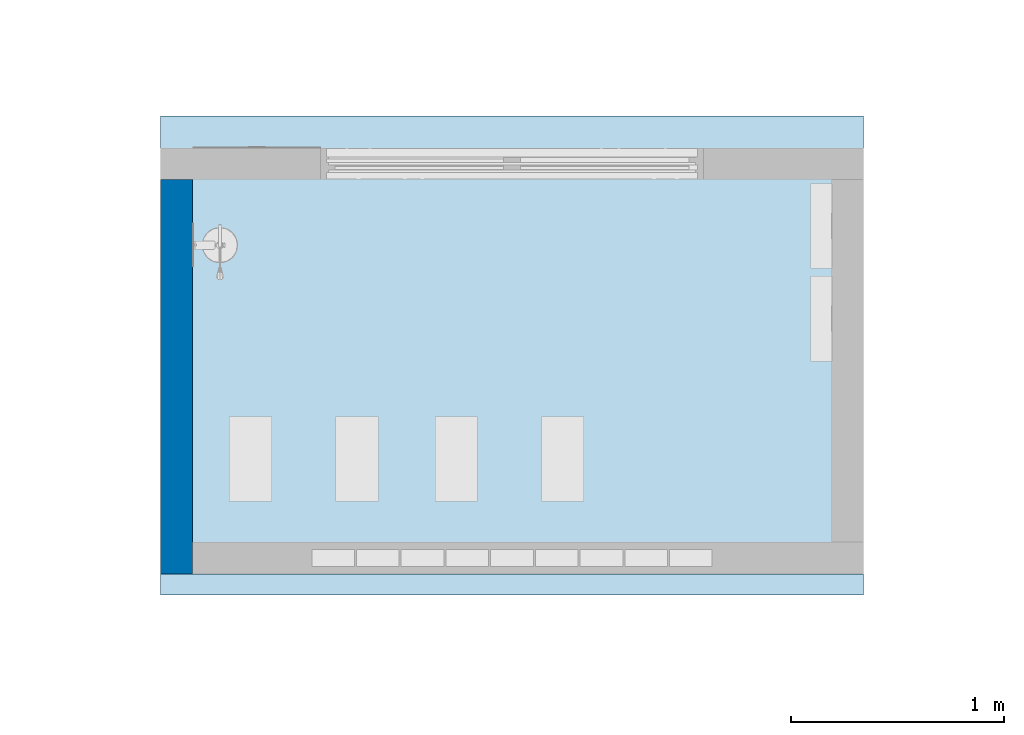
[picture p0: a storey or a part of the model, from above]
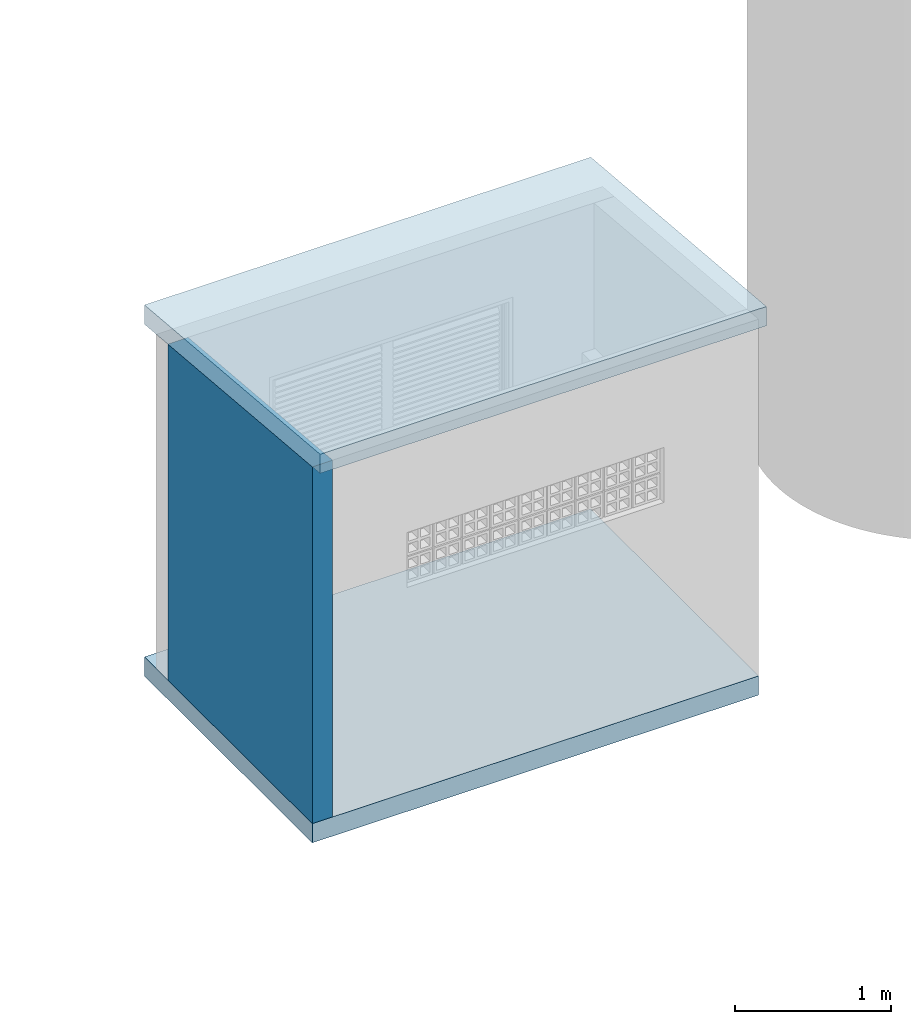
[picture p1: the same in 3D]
Properties of the parts of a building model (IFC2X3)

# File
Description: ViewDefinition [CoordinationView_V2.0]
File name: 0001
Time: 2022-03-27T23:40:12
Written by: The EXPRESS Data Manager Version 5.02.0100.07 : 28 Aug 2013
Made in: 21.1.60.25 - Exporter 21.1.60.25 - IU alternativa 21.1.60.25
Comment: STEP Physical File produced by: The EXPRESS Data Manager Version 5.02.0100.07 : 28 Aug 2013 * Module: EDMstepFileFactory/EDMstandAlone * Creation date: Sun Mar 27 23:40:12 2022 * Host: DESKTOP-MK1 * Database: C:\Users\kahal\AppData\Local\Temp\8a390837-8d56-472b-9c78-61db43efe1cc\653d68c4-2501-4b75-b9e8-e501fac27b86\ifc * Database version: 5507 * Database creation date: Sun Mar 27 23:39:55 2022 * Schema: IFC2X3 * Model: DataRepository.ifc * Model creation date: Sun Mar 27 23:39:55 2022 * Header model: DataRepository.ifc_HeaderModel * Header model creation date: Sun Mar 27 23:39:55 2022 * EDMuser: sdai-user * EDMgroup: sdai-group * License ID and type: 5605 : Permanent license. Expiry date: * EDMstepFileFactory options: 020000

# IfcProject, 0001
LongName: PROJETO DE SEGURANÇA CONTRA INCÊNDIO E PÂNICO; Phase: Status do projeto

# IfcSite, Default
RefLatitude: 42, 12, 46, 804504; RefLongitude: -71, -2, 0, -602416; RefElevation: 0 m

# IfcBuilding
Pset_BuildingCommon - NumberOfStoreys: 1

# IfcBuildingStorey: Nível:QDCG, PAV. 01 - TÉRREO
LongName: PAV. 01 - TÉRREO; Elevation: 0 m

# IfcBuildingElementProxy: CAIXA D'ÁGUA TIPO TUBULAR1:85m3 - TBL - 15,00m, CAIXA D'ÁGUA TIPO TUBULAR1:85m3 - TBL - 15,00m:11374999
In: PAV. 01 - TÉRREO
Type - Material: Material_reservatório
Type - Pset_BuildingElementProxyCommon - Reference: 85m3 - TBL - 15,00m
Type - Pset_QuantityTakeOff - Reference: 85m3 - TBL - 15,00m
Pset_BuildingElementProxyCommon - sets with these values: 2
Pset_ProvisionForVoid - Width: 15 m; Depth: 15 m

# IfcBuildingElementProxy: CAMINHÃO DE BOMBEIRO:CAMINHÃO DE BOMBEIRO, CAMINHÃO DE BOMBEIRO:CAMINHÃO DE BOMBEIRO:11451296
In: PAV. 01 - TÉRREO
Type - Material: Metal - Con capa pulverizada blanca
Type - Pset_BuildingElementProxyCommon - Reference: CAMINHÃO DE BOMBEIRO
Type - Pset_QuantityTakeOff - Reference: CAMINHÃO DE BOMBEIRO
Material: Metal - Con capa pulverizada blanca, Goma, Pintura - Extintor negro, Pintura - Extintor rojo, Metal - Aluminio, Fanalini rossi man, Body auto man, acciaio auto man, Fanalini arancioni man, Parti in plastica nere man, PINTURA CAMION RED, pedana martellata man, Nero ruote man, Acciaio cerchi man, Nero autocarro man, Vetro fari man, Vetro autocarro man
Pset_BuildingElementProxyCommon - sets with these values: 2

# IfcBuildingElementProxy: Elemento - E01-E02 - Alarme Sonoro + Comando manual do alarme:Alarme sonoro e botoeira do alarme (4)
In: PAV. 01 - TÉRREO
Type - Material: Plastico vermelho
Type - Pset_BuildingElementProxyCommon - Reference: Alarme sonoro e botoeira do alarme
Type - Pset_QuantityTakeOff - Reference: Alarme sonoro e botoeira do alarme
Material: Plastico vermelho, UHMW, White, Black, UHMW, Black, Plastic - Green Generic
Pset_BuildingElementProxyCommon - sets with these values: 2
Name (Elemento - E01-E02 - Alarme Sonoro + Comando manual do alarme:Alarme sonoro e botoeira do alarme:...)
11580355
11580449
11582165
11583381

# IfcBuildingElementProxy: Elemento - E03 - Comando manual de bomba:Botoeira da bomba (4)
In: PAV. 01 - TÉRREO
Type - Material: Plastico vermelho
Type - Pset_BuildingElementProxyCommon - Reference: Botoeira da bomba
Type - Pset_ManufacturerTypeInformation - Manufacturer: advCOMM
Type - Pset_QuantityTakeOff - Reference: Botoeira da bomba
Material: Plastico vermelho, UHMW, White, Black, UHMW, Black
Pset_BuildingElementProxyCommon - sets with these values: 2
Name (Elemento - E03 - Comando manual de bomba:Botoeira da bomba:...)
11580344
11580447
11582163
11583370

# IfcBuildingElementProxy: Elemento - E05 - Extintor:Extintor na parede - Carga de Pó ABC - 06Kg 3-A 20-BC (20)
In: PAV. 01 - TÉRREO
Type - Material: Plastico vermelho
Type - Pset_BuildingElementProxyCommon - Reference: Extintor na parede - Carga de Pó ABC - 06Kg 3-A 20-BC
Type - Pset_ManufacturerTypeInformation - Manufacturer: advCOMM
Type - Pset_QuantityTakeOff - Reference: Extintor na parede - Carga de Pó ABC - 06Kg 3-A 20-BC
Pset_BuildingElementProxyCommon - sets with these values: 2
Name (Elemento - E05 - Extintor:Extintor na parede - Carga de Pó ABC - 06Kg 3-A 20-BC:...) | Material
11374114 | Plastico vermelho, Plastico Amarelo, Pintura branca, Vidro, Pintura Metalica Vermelha, Metal Extintor, Borracha Cinza, Borracha preta, Plastico branco
11374170 | Plastico vermelho, Plastico Amarelo, Pintura branca, Vidro, Pintura Metalica Vermelha, Metal Extintor, Borracha Cinza, Borracha preta, Plastico branco
11565246 | Plastico vermelho, Plastico Amarelo, Pintura branca, Vidro, Pintura Metalica Vermelha, Metal Extintor, Borracha Cinza, Borracha preta, Plastico branco
11565351 | Plastico vermelho, Plastico Amarelo, Pintura branca, Vidro, Pintura Metalica Vermelha, Metal Extintor, Borracha Cinza, Borracha preta, Plastico branco
11578997 | Plastico vermelho, Plastico Amarelo, Metal Extintor, Borracha Cinza, Borracha preta, Plastico branco, Pintura Metalica Vermelha
11579091 | Plastico vermelho, Plastico Amarelo, Metal Extintor, Borracha Cinza, Borracha preta, Plastico branco, Pintura Metalica Vermelha
11579269 | Plastico vermelho, Plastico Amarelo, Metal Extintor, Borracha Cinza, Borracha preta, Plastico branco, Pintura Metalica Vermelha
11579494 | Plastico vermelho, Plastico Amarelo, Metal Extintor, Borracha Cinza, Borracha preta, Plastico branco, Pintura Metalica Vermelha
11580399 | Plastico vermelho, Plastico Amarelo, Metal Extintor, Borracha Cinza, Borracha preta, Plastico branco, Pintura Metalica Vermelha
11580481 | Plastico vermelho, Plastico Amarelo, Metal Extintor, Borracha Cinza, Borracha preta, Plastico branco, Pintura Metalica Vermelha
11580532 | Plastico vermelho, Plastico Amarelo, Metal Extintor, Borracha Cinza, Borracha preta, Plastico branco, Pintura Metalica Vermelha
11580586 | Plastico vermelho, Plastico Amarelo, Metal Extintor, Borracha Cinza, Borracha preta, Plastico branco, Pintura Metalica Vermelha
11581259 | Plastico vermelho, Plastico Amarelo, Metal Extintor, Borracha Cinza, Borracha preta, Plastico branco, Pintura Metalica Vermelha
11582185 | Plastico vermelho, Plastico Amarelo, Metal Extintor, Borracha Cinza, Borracha preta, Plastico branco, Pintura Metalica Vermelha
11583005 | Plastico vermelho, Plastico Amarelo, Metal Extintor, Borracha Cinza, Borracha preta, Plastico branco, Pintura Metalica Vermelha
11583127 | Plastico vermelho, Plastico Amarelo, Metal Extintor, Borracha Cinza, Borracha preta, Plastico branco, Pintura Metalica Vermelha
11583312 | Plastico vermelho, Plastico Amarelo, Metal Extintor, Borracha Cinza, Borracha preta, Plastico branco, Pintura Metalica Vermelha
11583412 | Plastico vermelho, Plastico Amarelo, Metal Extintor, Borracha Cinza, Borracha preta, Plastico branco, Pintura Metalica Vermelha
11583428 | Plastico vermelho, Plastico Amarelo, Metal Extintor, Borracha Cinza, Borracha preta, Plastico branco, Pintura Metalica Vermelha
11583605 | Plastico vermelho, Plastico Amarelo, Metal Extintor, Borracha Cinza, Borracha preta, Plastico branco, Pintura Metalica Vermelha

# IfcBuildingElementProxy: Elemento - E05 - Extintor:Extintor na parede - Carga de Pó BC - 06Kg 20-BC, Elemento - E05 - Extintor:Extintor na parede - Carga de Pó BC - 06Kg 20-BC:11376019
In: PAV. 01 - TÉRREO
Type - Material: Metal Extintor
Type - Pset_BuildingElementProxyCommon - Reference: Extintor na parede - Carga de Pó BC - 06Kg 20-BC
Type - Pset_ManufacturerTypeInformation - Manufacturer: advCOMM
Type - Pset_QuantityTakeOff - Reference: Extintor na parede - Carga de Pó BC - 06Kg 20-BC
Material: Metal Extintor, Borracha Cinza, Borracha preta, Plastico branco, Pintura Metalica Vermelha
Pset_BuildingElementProxyCommon - sets with these values: 2

# IfcBuildingElementProxy: Elemento - E05 - Extintor:Extintor na parede - Carga de Pó BC - 06Kg 20-BC, Elemento - E05 - Extintor:Extintor na parede - Carga de Pó BC - 06Kg 20-BC:11578051
In: PAV. 01 - TÉRREO
Type - Material: Pintura branca
Type - Pset_BuildingElementProxyCommon - Reference: Extintor na parede - Carga de Pó BC - 06Kg 20-BC
Type - Pset_ManufacturerTypeInformation - Manufacturer: advCOMM
Type - Pset_QuantityTakeOff - Reference: Extintor na parede - Carga de Pó BC - 06Kg 20-BC
Material: Pintura branca, Vidro, Pintura Metalica Vermelha, Metal Extintor, Borracha Cinza, Borracha preta, Plastico branco
Pset_BuildingElementProxyCommon - sets with these values: 2

# IfcBuildingElementProxy: Elemento - E05 - Extintor:Extintor no piso - Carga de Pó ABC - 06Kg 3-A 20-BC, Elemento - E05 - Extintor:Extintor no piso - Carga de Pó ABC - 06Kg 3-A 20-BC:11374217
In: PAV. 01 - TÉRREO
Type - Material: Plastico vermelho
Type - Pset_BuildingElementProxyCommon - Reference: Extintor no piso - Carga de Pó ABC - 06Kg 3-A 20-BC
Type - Pset_ManufacturerTypeInformation - Manufacturer: advCOMM
Type - Pset_QuantityTakeOff - Reference: Extintor no piso - Carga de Pó ABC - 06Kg 3-A 20-BC
Material: Plastico vermelho, Plastico Amarelo, Borracha Cinza, Borracha preta, Metal Extintor, Plastico branco, Pintura Metalica Vermelha, Cromado, Pintura branca, Vidro
Pset_BuildingElementProxyCommon - sets with these values: 2

# IfcBuildingElementProxy: Equipamento - Bomba de Incêndio:Bomba de Incêndio Genérica (4)
In: PAV. 01 - TÉRREO
Type - Pset_BuildingElementProxyCommon - Reference: Bomba de Incêndio Genérica
Type - Pset_ManufacturerTypeInformation - Manufacturer: advCOMM
Type - Pset_QuantityTakeOff - Reference: Bomba de Incêndio Genérica
Pset_BuildingElementProxyCommon - sets with these values: 2
Name (Equipamento - Bomba de Incêndio:Bomba de Incêndio Genérica:...)
11375908 | Pset_ProvisionForVoid - Width: 0.3 m; Height: 0.4 m; Depth: 0.3 m
11375923
11375931
11375939

# IfcBuildingElementProxy: Equipamento - Central de Alarme e Detecção de Incêndio:Central de Alarme e Detecção de Incêndio, Equipamento - Central de Alarme e Detecção de Incêndio:Central de Alarme e Detecção de Incêndio:11376524
In: PAV. 01 - TÉRREO
Type - Material: Plastico branco
Type - Pset_BuildingElementProxyCommon - Reference: Central de Alarme e Detecção de Incêndio
Type - Pset_QuantityTakeOff - Reference: Central de Alarme e Detecção de Incêndio
Pset_BuildingElementProxyCommon - sets with these values: 2

# IfcBuildingElementProxy: Equipamento - Detector pontual de incêndio:Detector de calor pontual (parede) (4)
In: PAV. 01 - TÉRREO
Type - Material: Plastic - White Generic
Type - Pset_BuildingElementProxyCommon - Reference: Detector de calor pontual (parede)
Type - Pset_QuantityTakeOff - Reference: Detector de calor pontual (parede)
Pset_BuildingElementProxyCommon - sets with these values: 2
Name (Equipamento - Detector pontual de incêndio:Detector de calor pontual (parede):...)
11586347
11586350
11586353
11586356

# IfcBuildingElementProxy: Equipamento - E07 - Hidrante:Hidrante de recalque embutido - 2.1/2, Equipamento - E07 - Hidrante:Hidrante de recalque embutido - 2.1/2:11579980
In: PAV. 01 - TÉRREO
Type - Material: Pintura Metalica Vermelha, Pintura branca
Type - Pset_BuildingElementProxyCommon - Reference: Hidrante de recalque embutido - 2.1/2
Type - Pset_QuantityTakeOff - Reference: Hidrante de recalque embutido - 2.1/2
Material: Pintura branca, Vidro, Pintura Metalica Vermelha
Pset_BuildingElementProxyCommon - sets with these values: 2

# IfcBuildingElementProxy: Equipamento - E07 - Hidrante:Hidrante simples embutido - requinte 2.1/2 - 38 mm - 30m (4)
In: PAV. 01 - TÉRREO
Type - Material: Pintura Metalica Vermelha, Pintura branca
Type - Pset_BuildingElementProxyCommon - Reference: Hidrante simples embutido - requinte 2.1/2 - 38 mm - 30m
Type - Pset_QuantityTakeOff - Reference: Hidrante simples embutido - requinte 2.1/2 - 38 mm - 30m
Material: Pintura branca, Vidro, Pintura Metalica Vermelha
Pset_BuildingElementProxyCommon - sets with these values: 2
Name (Equipamento - E07 - Hidrante:Hidrante simples embutido - requinte 2.1/2 - 38 mm - 30m:...)
11579944
11579956
11579968
11583357

# IfcBuildingElementProxy: Equipamento - Luminaria de Emergência:Luminaria - 5 LUX (74)
In: PAV. 01 - TÉRREO
Type - Material: LED
Type - Pset_BuildingElementProxyCommon - Reference: Luminaria - 5 LUX
Type - Pset_QuantityTakeOff - Reference: Luminaria - 5 LUX
Material: LED, Plástico Branco
Pset_BuildingElementProxyCommon - sets with these values: 2
Name (Equipamento - Luminaria de Emergência:Luminaria - 5 LUX:...)
11376487
11376589
11567384
11567395
11567400
11568110
11568125
11568230
11568334
11568349
11568480
11568617
11568695
11570228
11570244
11570259
11570285
11579053
11579086
11579115
11579153
11579182
11579211
11579238
11580893
11580894
11580918
11580919
11581328
11581329
11581747
11581748
11581772
11581773
11582111
11582112
11582506
11582507
11582562
11582563
11582612
11582613
11582637
11582638
11582662
11582663
11582691
11582692
11582718
11582719
11582747
11582748
11582859
11582860
11582896
11582897
11582945
11582946
11582971
11582972
11583114
11583115
11583237
11583238
11583258
11583259
11583285
11583286
11583838
11583839
11583865
11583866
11583901
11583902

# IfcBuildingElementProxy: Indicação de Obstáculos:Indicador - O01 - Amarelo (ambiente interno) (188)
In: PAV. 01 - TÉRREO
Type - Material: O_01_amarelo, O_01_Preto, Plastico Amarelo
Type - Pset_BuildingElementProxyCommon - Reference: Indicador - O01 - Amarelo (ambiente interno)
Type - Pset_QuantityTakeOff - Reference: Indicador - O01 - Amarelo (ambiente interno)
Material: Plastico Amarelo, Plastico Preto, O_01_amarelo, O_01_Preto
Pset_BuildingElementProxyCommon - sets with these values: 2
Name (Indicação de Obstáculos:Indicador - O01 - Amarelo (ambiente interno):...)
11566434
11566435
11566444
11566445
11566456
11566457
11567014
11567015
11579049
11579050
11579051
11579052
11579082
11579083
11579084
11579085
11579111
11579112
11579113
11579114
11579149
11579150
11579151
11579152
11579178
11579179
11579180
11579181
11579207
11579208
11579209
11579210
11579234
11579235
11579236
11579237
11579638
11579639
11579640
11579641
11579665
11579666
11579667
11579668
11579684
11579685
11579686
11579687
11579701
11579702
11579703
11579704
11579716
11579717
11579718
11579719
11579733
11579734
11579735
11579736
11579750
11579751
11579752
11579753
11579767
11579768
11579769
11579770
11580889
11580890
11580891
11580892
11580914
11580915
11580916
11580917
11581324
11581325
11581326
11581327
11581743
11581744
11581745
11581746
11581768
11581769
11581770
11581771
11582107
11582108
11582109
11582110
11582213
11582216
11582502
11582503
11582504
11582505
11582558
11582559
11582560
11582561
11582608
11582609
11582610
11582611
11582633
11582634
11582635
11582636
11582658
11582659
11582660
11582661
11582687
11582688
11582689
11582690
11582714
11582715
11582716
11582717
11582743
11582744
11582745
11582746
11582855
11582856
11582857
11582858
11582892
11582893
11582894
11582895
11582941
11582942
11582943
11582944
11582967
11582968
11582969
11582970
11583110
11583111
11583112
11583113
11583233
11583234
11583235
11583236
11583254
11583255
11583256
11583257
11583281
11583282
11583283
11583284
11583473
11583474
11583475
11583476
11583500
11583501
11583502
11583503
11583532
11583533
11583534
11583535
11583771
11583774
11583777
11583780
11583783
11583786
11583834
11583835
11583836
11583837
11583861
11583862
11583863
11583864
11583897
11583898
11583899
11583900

# IfcBuildingElementProxy: Sinalização Básica - M02:Sinalização - Placa - M02 (2)
In: PAV. 01 - TÉRREO
Type - Material: Plástico Branco
Type - Pset_BuildingElementProxyCommon - Reference: Sinalização - Placa - M02
Type - Pset_QuantityTakeOff - Reference: Sinalização - Placa - M02
Material: Plástico Branco, Plástico Verde
Pset_BuildingElementProxyCommon - sets with these values: 2
Name (Sinalização Básica - M02:Sinalização - Placa - M02:...)
11569015 | Pset_ProvisionForVoid - Width: 0.45 m; Height: 0.738708 m; Depth: 0.45 m
11580674

# IfcBuildingElementProxy: Sinalização Básica - Ponto de Encontro da Brigada:450X450MM, Sinalização Básica - Ponto de Encontro da Brigada:450X450MM:11588753
In: PAV. 01 - TÉRREO
Type - Material: Plástico Branco
Type - Pset_BuildingElementProxyCommon - Reference: 450X450MM
Type - Pset_QuantityTakeOff - Reference: 450X450MM
Material: Plástico Branco, Plastico vermelho
Pset_BuildingElementProxyCommon - sets with these values: 2
Pset_ProvisionForVoid - Width: 0.45 m; Height: 0.45 m; Depth: 0.45 m

# IfcBuildingElementProxy: Sinalização Complementar - M01:450x450MM (2)
In: PAV. 01 - TÉRREO
Type - Material: Plástico Branco
Type - Pset_BuildingElementProxyCommon - Reference: 450x450MM
Type - Pset_QuantityTakeOff - Reference: 450x450MM
Material: Plástico Branco, Plástico Verde
Pset_BuildingElementProxyCommon - sets with these values: 2
Name (Sinalização Complementar - M01:450x450MM:...)
11568855
11580673

# IfcBuildingElementProxy: Sinalização de Alerta - A01 - Alerta geral:Distância 20m, Sinalização de Alerta - A01 - Alerta geral:Distância 20m:11374964
In: PAV. 01 - TÉRREO
Type - Material: Plastico Amarelo
Type - Pset_BuildingElementProxyCommon - Reference: Distância 20m
Type - Pset_ManufacturerTypeInformation - Manufacturer: advCOMM
Type - Pset_QuantityTakeOff - Reference: Distância 20m
Material: Plastico Amarelo, Plastico Preto
Pset_BuildingElementProxyCommon - sets with these values: 2
Pset_ProvisionForVoid - Width: 0.001 m; Depth: 0.001 m

# IfcBuildingElementProxy: Sinalização de equipamentos - B01 - Alimentação da Bomba:Placa 150x200 (2)
In: PAV. 01 - TÉRREO
Type - Material: Plastico branco
Type - Pset_BuildingElementProxyCommon - Reference: Placa 150x200
Type - Pset_QuantityTakeOff - Reference: Placa 150x200
Material: Plastico branco, Plastico vermelho, Telhado padrão
Pset_BuildingElementProxyCommon - sets with these values: 2
Name (Sinalização de equipamentos - B01 - Alimentação da Bomba:Placa 150x200:...)
11375968 | Pset_ProvisionForVoid - Width: 0.4 m; Height: 0.1 m; Depth: 0.4 m
11375986

# IfcBuildingElementProxy: Sinalização de equipamentos - E01 - Alarme sonoro:Distância 08m (4)
In: PAV. 01 - TÉRREO
Type - Material: Plastico branco
Type - Pset_BuildingElementProxyCommon - Reference: Distância 08m
Type - Pset_ManufacturerTypeInformation - Manufacturer: advCOMM
Type - Pset_QuantityTakeOff - Reference: Distância 08m
Material: Plastico branco, Plastico vermelho
Pset_BuildingElementProxyCommon - sets with these values: 2
Name (Sinalização de equipamentos - E01 - Alarme sonoro:Distância 08m:...)
11580356 | Pset_ProvisionForVoid - Width: 0.001 m; Height: 0.2 m; Depth: 0.001 m
11580450
11582166
11583382

# IfcBuildingElementProxy: Sinalização de equipamentos - E02 - Comando manual de alarme:Distância 08m (4)
In: PAV. 01 - TÉRREO
Type - Material: Plastico branco
Type - Pset_BuildingElementProxyCommon - Reference: Distância 08m
Type - Pset_ManufacturerTypeInformation - Manufacturer: advCOMM
Type - Pset_QuantityTakeOff - Reference: Distância 08m
Material: Plastico branco, Plastico vermelho
Pset_BuildingElementProxyCommon - sets with these values: 2
Name (Sinalização de equipamentos - E02 - Comando manual de alarme:Distância 08m:...)
11580357 | Pset_ProvisionForVoid - Width: 0.001 m; Height: 0.2 m; Depth: 0.001 m
11580451
11582167
11583383

# IfcBuildingElementProxy: Sinalização de equipamentos - E03 - Comando manual de alarme ou bomba de incêndio:Distância 08m (4)
In: PAV. 01 - TÉRREO
Type - Material: Plastico branco
Type - Pset_BuildingElementProxyCommon - Reference: Distância 08m
Type - Pset_ManufacturerTypeInformation - Manufacturer: advCOMM
Type - Pset_QuantityTakeOff - Reference: Distância 08m
Material: Plastico branco, Plastico vermelho
Pset_BuildingElementProxyCommon - sets with these values: 2
Name (Sinalização de equipamentos - E03 - Comando manual de alarme ou bomba de incêndio:Distância 08m:...)
11580345 | Pset_ProvisionForVoid - Width: 0.001 m; Height: 0.2 m; Depth: 0.001 m
11580448
11582164
11583371

# IfcBuildingElementProxy: Sinalização de equipamentos - E05 - Extintor de incêndio - TIPO 2:Placa de extintor - E6-A (23)
In: PAV. 01 - TÉRREO
Type - Material: Plastico Preto
Type - Pset_BuildingElementProxyCommon - Reference: Placa de extintor - E6-A
Type - Pset_QuantityTakeOff - Reference: Placa de extintor - E6-A
Material: Plastico Preto, Plastico azul claro, Plastico vermelho, Plastico branco, Plastico Verde
Pset_BuildingElementProxyCommon - sets with these values: 2
Name (Sinalização de equipamentos - E05 - Extintor de incêndio - TIPO 2:Placa de extintor - E6-A:...)
11374116 | Pset_ProvisionForVoid - Width: 0.0169977 m; Height: 0.182 m; Depth: 0.0169977 m
11374172
11374219
11376021
11565248
11565353
11578053
11578999
11579093
11579271 | Pset_ProvisionForVoid - Width: 0.0169977 m; Height: 0.001 m; Depth: 0.0169977 m
11579496
11580401
11580483
11580534
11580588
11581261
11582187
11583007
11583129
11583314
11583414
11583430
11583607

# IfcBuildingElementProxy: Sinalização de equipamentos - E05 - Extintor de incêndio:Distância 08m (23)
In: PAV. 01 - TÉRREO
Type - Material: Plastico branco
Type - Pset_BuildingElementProxyCommon - Reference: Distância 08m
Type - Pset_ManufacturerTypeInformation - Manufacturer: advCOMM
Type - Pset_QuantityTakeOff - Reference: Distância 08m
Material: Plastico branco, Plastico vermelho
Pset_BuildingElementProxyCommon - sets with these values: 2
Name (Sinalização de equipamentos - E05 - Extintor de incêndio:Distância 08m:...)
11374115 | Pset_ProvisionForVoid - Width: 0.001 m; Height: 0.2 m; Depth: 0.001 m
11374171
11374218
11376020
11565247
11565352
11578052
11578998
11579092
11579270 | Pset_ProvisionForVoid - Width: 0.001 m; Height: 0.2 m; Depth: 0.001 m
11579495
11580400
11580482
11580533
11580587
11581260
11582186
11583006
11583128
11583313
11583413
11583429
11583606

# IfcBuildingElementProxy: Sinalização de equipamentos - E07 - Abrigo de mangueira e hidrante:Distância 08m (5)
In: PAV. 01 - TÉRREO
Type - Material: Plastico branco
Type - Pset_BuildingElementProxyCommon - Reference: Distância 08m
Type - Pset_ManufacturerTypeInformation - Manufacturer: advCOMM
Type - Pset_QuantityTakeOff - Reference: Distância 08m
Material: Plastico branco, Plastico vermelho
Pset_BuildingElementProxyCommon - sets with these values: 2
Name (Sinalização de equipamentos - E07 - Abrigo de mangueira e hidrante:Distância 08m:...)
11579946 | Pset_ProvisionForVoid - Width: 0.001 m; Height: 0.2 m; Depth: 0.001 m
11579958
11579970
11579982
11583359

# IfcBuildingElementProxy: Sinalização de equipamentos - E08 - Hidrante de incêndio:Distância 08m (5)
In: PAV. 01 - TÉRREO
Type - Material: Plastico branco
Type - Pset_BuildingElementProxyCommon - Reference: Distância 08m
Type - Pset_ManufacturerTypeInformation - Manufacturer: advCOMM
Type - Pset_QuantityTakeOff - Reference: Distância 08m
Material: Plastico branco, Plastico vermelho
Pset_BuildingElementProxyCommon - sets with these values: 2
Name (Sinalização de equipamentos - E08 - Hidrante de incêndio:Distância 08m:...)
11579945 | Pset_ProvisionForVoid - Width: 0.001 m; Height: 0.2 m; Depth: 0.001 m
11579957
11579969
11579981
11583358

# IfcBuildingElementProxy: Sinalização de orientação - S01 - Indicação do sentido da saída de emergência direita:Distância 12m (25)
In: PAV. 01 - TÉRREO
Type - Material: Plastico branco
Type - Pset_BuildingElementProxyCommon - Reference: Distância 12m
Type - Pset_ManufacturerTypeInformation - Manufacturer: advCOMM
Type - Pset_QuantityTakeOff - Reference: Distância 12m
Material: Plastico branco, Plastico Verde
Pset_BuildingElementProxyCommon - sets with these values: 2
Name (Sinalização de orientação - S01 - Indicação do sentido da saída de emergência direita:Distância 12m:...)
11567414 | Pset_ProvisionForVoid - Width: 0.0011 m; Height: 0.38 m; Depth: 0.0011 m
11568087 | Pset_ProvisionForVoid - Width: 0.0011 m; Height: 0.38 m; Depth: 0.0011 m
11568102
11569904
11580895
11580920
11581378
11581757
11581782
11582572
11582622
11582647
11582672
11582701
11582728
11582757
11582928
11582954
11582973
11582980
11583124
11583264
11583291
11583871
11583962

# IfcBuildingElementProxy: Sinalização de orientação - S01 - Indicação do sentido da saída de emergência direita:Distância 20m (7)
In: PAV. 01 - TÉRREO
Type - Material: Plastico branco
Type - Pset_BuildingElementProxyCommon - Reference: Distância 20m
Type - Pset_ManufacturerTypeInformation - Manufacturer: advCOMM
Type - Pset_QuantityTakeOff - Reference: Distância 20m
Material: Plastico branco, Plastico Verde
Pset_BuildingElementProxyCommon - sets with these values: 2
Name (Sinalização de orientação - S01 - Indicação do sentido da saída de emergência direita:Distância 20m:...)
11567385 | Pset_ProvisionForVoid - Width: 0.0011 m; Height: 0.632 m; Depth: 0.0011 m
11568076 | Pset_ProvisionForVoid - Width: 0.0011 m; Height: 0.632 m; Depth: 0.0011 m
11578903
11579054
11579087
11579116
11583815

# IfcBuildingElementProxy: Sinalização de orientação - S02 - Indicação do sentido da saída de emergência esquerda:Distância 12m (25)
In: PAV. 01 - TÉRREO
Type - Material: Plastico branco
Type - Pset_BuildingElementProxyCommon - Reference: Distância 12m
Type - Pset_ManufacturerTypeInformation - Manufacturer: advCOMM
Type - Pset_QuantityTakeOff - Reference: Distância 12m
Material: Plastico branco, Plastico Verde
Pset_BuildingElementProxyCommon - sets with these values: 2
Name (Sinalização de orientação - S02 - Indicação do sentido da saída de emergência esquerda:Distância 12m:...)
11567461 | Pset_ProvisionForVoid - Width: 0.0011 m; Height: 0.001 m; Depth: 0.0011 m
11568311
11568325
11568685
11569173 | Pset_ProvisionForVoid - Width: 0.0011 m; Height: 0.001 m; Depth: 0.0011 m
11580896
11580921
11581331
11581749
11581774
11582113
11582564
11582614
11582639
11582664
11582693
11582720
11582749
11582898
11582947
11583116
11583207
11583243
11583907
11583942

# IfcBuildingElementProxy: Sinalização de orientação - S02 - Indicação do sentido da saída de emergência esquerda:Distância 20m (7)
In: PAV. 01 - TÉRREO
Type - Material: Plastico branco
Type - Pset_BuildingElementProxyCommon - Reference: Distância 20m
Type - Pset_ManufacturerTypeInformation - Manufacturer: advCOMM
Type - Pset_QuantityTakeOff - Reference: Distância 20m
Material: Plastico branco, Plastico Verde
Pset_BuildingElementProxyCommon - sets with these values: 2
Name (Sinalização de orientação - S02 - Indicação do sentido da saída de emergência esquerda:Distância 20m:...)
11568065 | Pset_ProvisionForVoid - Width: 0.0011 m; Height: 0.001 m; Depth: 0.0011 m
11579154 | Pset_ProvisionForVoid - Width: 0.0011 m; Height: 0.001 m; Depth: 0.0011 m
11579183
11579212
11579239
11579279
11583805

# IfcBuildingElementProxy: Sinalização de orientação - S03 - Indicação de uma saída de emergência a ser afixada acima da porta:Distância 12m (3)
In: PAV. 01 - TÉRREO
Type - Material: Plastico branco
Type - Pset_BuildingElementProxyCommon - Reference: Distância 12m
Type - Pset_ManufacturerTypeInformation - Manufacturer: advCOMM
Type - Pset_QuantityTakeOff - Reference: Distância 12m
Material: Plastico branco, Plastico Verde
Pset_BuildingElementProxyCommon - sets with these values: 2
Name (Sinalização de orientação - S03 - Indicação de uma saída de emergência a ser afixada acima da porta:Distância 12m:...)
11568133 | Pset_ProvisionForVoid - Width: 0.001 m; Height: 0.395 m; Depth: 0.001 m
11568367
11568548

# IfcBuildingElementProxy: Sinalização de orientação - S03 - Indicação de uma saída de emergência a ser afixada acima da porta:Distância 20m, Sinalização de orientação - S03 - Indicação de uma saída de emergência a ser afixada acima da porta:Distância 20m:11567982
In: PAV. 01 - TÉRREO
Type - Material: Plastico branco
Type - Pset_BuildingElementProxyCommon - Reference: Distância 20m
Type - Pset_ManufacturerTypeInformation - Manufacturer: advCOMM
Type - Pset_QuantityTakeOff - Reference: Distância 20m
Material: Plastico branco, Plastico Verde
Pset_BuildingElementProxyCommon - sets with these values: 2
Pset_ProvisionForVoid - Width: 0.001 m; Height: 0.647 m; Depth: 0.001 m

# IfcBuildingElementProxy: Sinalização de orientação - S12 - Saída de emergência:Distância 12m (6)
In: PAV. 01 - TÉRREO
Type - Material: Plastico branco
Type - Pset_BuildingElementProxyCommon - Reference: Distância 12m
Type - Pset_ManufacturerTypeInformation - Manufacturer: advCOMM
Type - Pset_QuantityTakeOff - Reference: Distância 12m
Material: Plastico branco, Plastico Verde
Pset_BuildingElementProxyCommon - sets with these values: 2
Name (Sinalização de orientação - S12 - Saída de emergência:Distância 12m:...)
11376547 | Pset_ProvisionForVoid - Width: 0.001 m; Height: 0.395 m; Depth: 0.001 m
11376590
11570229
11570245
11570260
11570286

# IfcBuildingElementProxy: Sinalização de orientação - S12 - Saída de emergência:Distância 20m (8)
In: PAV. 01 - TÉRREO
Type - Material: Plastico branco
Type - Pset_BuildingElementProxyCommon - Reference: Distância 20m
Type - Pset_ManufacturerTypeInformation - Manufacturer: advCOMM
Type - Pset_QuantityTakeOff - Reference: Distância 20m
Material: Plastico branco, Plastico Verde
Pset_BuildingElementProxyCommon - sets with these values: 2
Name (Sinalização de orientação - S12 - Saída de emergência:Distância 20m:...)
11569188 | Pset_ProvisionForVoid - Width: 0.001 m; Height: 0.647 m; Depth: 0.001 m
11582239
11582282
11582302
11583625
11583635
11583649
11583665

# IfcDoor: Correr - 1 folha - Veneziana:1.80x2.10, Correr - 1 folha - Veneziana:1.80x2.10:11430144
In: PAV. 01 - TÉRREO
Type - ParameterTakesPrecedence: no; Sizeable: no; Material: ALUMÍNIO COM PINTURA ELETROSTÁTICA BRANCA
Type - Pset_DoorCommon - IsExternal: no; Reference: 1.80x2.10
Type - Pset_QuantityTakeOff - Reference: 1.80x2.10
OverallHeight: 2.1 m; OverallWidth: 1.8 m

# IfcRoof: Telhado básico:Genérico - 150 mm, Telhado básico:Genérico - 150 mm:11430147
In: PAV. 01 - TÉRREO
Pset_QuantityTakeOff - Reference: Genérico - 150 mm
Pset_RoofCommon - IsExternal: yes; Reference: Genérico - 150 mm; ProjectedArea: 7.425 m2; TotalArea: 7.45336 m2

# IfcSlab: Piso:Genérico 150 mm, Piso:Genérico 150 mm:11430138
In: PAV. 01 - TÉRREO
Type - PredefinedType: FLOOR; Material: Concreto, Moldado in loco 0.15 m
Type - Pset_QuantityTakeOff - Reference: Genérico 150 mm
Type - Pset_ReinforcementBarPitchOfSlab - Reference: Genérico 150 mm
Type - Pset_SlabCommon - IsExternal: no; Reference: Genérico 150 mm; ThermalTransmittance: 6.97333 kg/K/s3
Pset_QuantityTakeOff - sets with these values: 2
Pset_SlabCommon - LoadBearing: no; PitchAngle: 0 deg

# IfcSlab: Telhado básico:Genérico - 150 mm, Telhado básico:Genérico - 150 mm:11430147
In: PAV. 01 - TÉRREO
Type - PredefinedType: ROOF
Type - Pset_QuantityTakeOff - Reference: Genérico - 150 mm
Type - Pset_ReinforcementBarPitchOfSlab - Reference: Genérico - 150 mm
Type - Pset_SlabCommon - IsExternal: yes; Reference: Genérico - 150 mm; ThermalTransmittance: 6.97333 kg/K/s3
Material: Concreto, Moldado in loco; Concreto, Moldado in loco 0.15 m
Pset_QuantityTakeOff - sets with these values: 2
Pset_SlabCommon - PitchAngle: 5 deg

# IfcWallStandardCase: Parede básica:Parede 15 - Externa (4)
In: PAV. 01 - TÉRREO
Type - PredefinedType: STANDARD; Material: Alvenaria - Reboco 0.025 m, Alvenaria - Tijolo 8 furos 0.1 m, Alvenaria - Reboco 0.025 m
Type - Pset_QuantityTakeOff - Reference: Parede 15 - Externa
Type - Pset_ReinforcementBarPitchOfWall - Reference: Parede 15 - Externa
Type - Pset_WallCommon - Reference: Parede 15 - Externa; IsExternal: no
Pset_QuantityTakeOff - sets with these values: 2
Pset_WallCommon - IsExternal: yes; ExtendToStructure: yes; LoadBearing: no
Name (Parede básica:Parede 15 - Externa:...)
11430132
11430133
11430134
11430135

# IfcWindow: Elemento Vazado:COB Window 11B, Elemento Vazado:COB Window 11B:11430156
In: PAV. 01 - TÉRREO
Type - ParameterTakesPrecedence: no; Sizeable: no
Type - Pset_QuantityTakeOff - Reference: COB Window 11B
Type - Pset_WindowCommon - IsExternal: no; Reference: COB Window 11B
OverallHeight: 0.43 m; OverallWidth: 1.9 m
Pset_WindowCommon - IsExternal: yes
